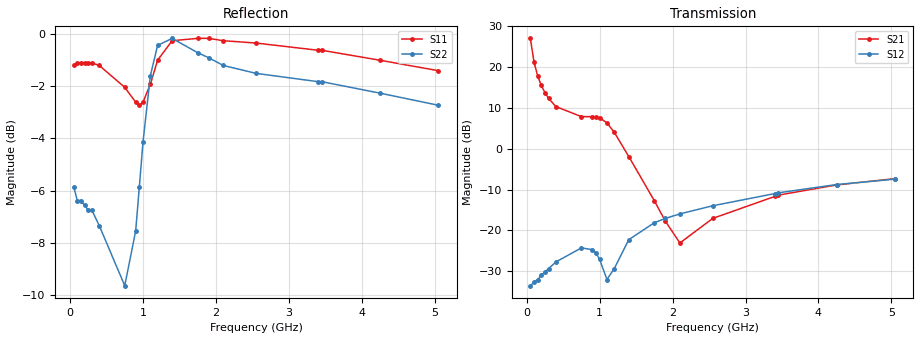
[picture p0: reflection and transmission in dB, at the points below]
!AT-33225
!S-PARAMETERS at Vce=6.0V  Ic=100mA.  LAST UPDATED 08-05-96
# ghz s ma r 50
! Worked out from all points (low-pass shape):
!   101 points, 50 MHz to 5.05 GHz, reference 50 ohm
!   highest |S21| = 27.03 dB at 50 MHz (marker M1); lowest = -23.1 dB at 2.1 GHz (marker M2)
!   |S21| within 3 dB of the highest: start of sweep to 76 MHz
!   lowest |S11| = -2.7 dB at 950 MHz (marker M3), VSWR 6.41, Z = 7.82 + j2.56 ohm
!   |S11| at or under -10 dB: nowhere
!   |S22| runs from -9.6 to -0.1 dB; largest |S21 - S12| = 22
!   S11 on the Smith chart (normalised r, x): 50 MHz: 0.07, -0.18; 400 MHz: 0.07, +0.04; 1.9 GHz: 0.01, +0.18; 3.45 GHz: 0.04, +0.37; 5.05 GHz: 0.11, +0.60
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0.05  0.87 -159.0  22.46 101.0  0.021 24.0  0.51 -143.0
0.1  0.88 -171.0  11.56 91.0  0.023 27.0  0.48 -162.0
0.15  0.88 -176.0  7.82 86.0  0.025 32.0  0.48 -169.0
0.2  0.88 -178.0  5.95 82.0  0.028 37.0  0.47 -172.0
0.25  0.88 180.0  4.86 78.0  0.031 40.0  0.46 -175.0
0.3  0.88 178.0  4.14 74.0  0.034 43.0  0.46 -176.0
0.4  0.87 175.0  3.28 67.0  0.041 46.0  0.43 -178.0
0.75  0.79 170.0  2.47 36.0  0.061 38.0  0.33 -161.0
0.9  0.74 172.0  2.47 13.0  0.058 27.0  0.42 -135.0
0.95  0.73 174.0  2.45 3.0  0.053 23.0  0.51 -132.0
1  0.74 176.0  2.39 -8.0  0.044 21.0  0.62 -132.0
1.1  0.8 180.0  2.07 -33.0  0.025 40.0  0.83 -141.0
1.2  0.89 179.0  1.59 -55.0  0.034 89.0  0.95 -154.0
1.4  0.97 172.0  0.8 -86.0  0.077 91.0  0.98 -172.0
1.75  0.98 163.0  0.23 -122.0  0.124 79.0  0.92 172.0
1.9  0.98 160.0  0.13 -142.0  0.14 75.0  0.9 168.0
2.1  0.97 157.0  0.07 162.0  0.159 71.0  0.87 163.0
2.55  0.96 151.0  0.14 82.0  0.2 63.0  0.84 154.0
3.4  0.93 140.0  0.26 54.0  0.282 50.0  0.81 138.0
3.45  0.93 139.0  0.27 52.0  0.288 49.0  0.81 137.0
4.25  0.89 128.0  0.36 35.0  0.364 33.0  0.77 118.0
5.05  0.85 118.0  0.43 18.0  0.424 18.0  0.73 96.0
